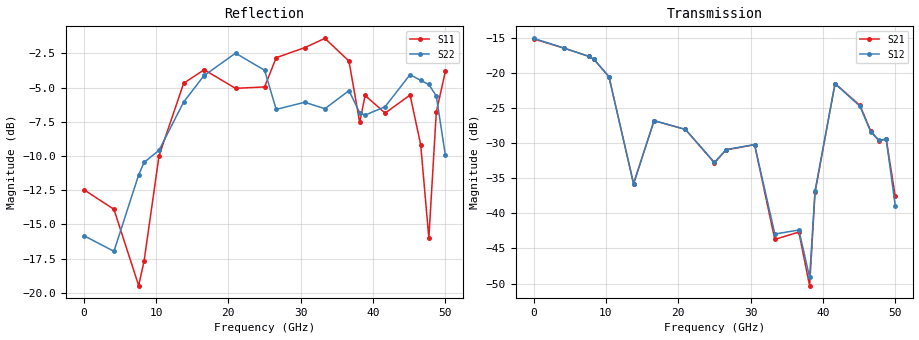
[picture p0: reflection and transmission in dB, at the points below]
!Keysight Technologies,N5245B,MY58422270,A.16.20.02
!Date: Thursday, March 05, 2026 01:11:40
!Correction: S11(C  2-Port  )
!S21(C  2-Port  )
!S12(C  2-Port  )
!S22(C  2-Port  )
!S2P File: Measurements: S11, S21, S12, S22:
# Hz S  dB  R 50
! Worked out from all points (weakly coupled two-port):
!   3201 points, 10 MHz to 50 GHz, reference 50 ohm
!   highest |S21| = -15.19 dB at 10 MHz (marker M1); lowest = -50.3 dB at 38.16 GHz (marker M2)
!   lowest |S11| = -19.5 dB at 7.602 GHz (marker M3), VSWR 1.24, Z = 40.5 - j1.37 ohm
!   |S11| at or under -10 dB: start of sweep to 10.41 GHz; 46.72 GHz to 48.26 GHz (1.535 GHz wide, 3.23 % of centre)
!   |S22| runs from -20.2 to -2.5 dB; largest |S21 - S12| = 0.0035
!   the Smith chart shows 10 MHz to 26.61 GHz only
!   S11 on the Smith chart (normalised r, x): 10 MHz: 1.62, -0.03; 10.41 GHz: 0.54, +0.15; 13.82 GHz: 1.13, +1.52; 16.63 GHz: 1.33, -1.96; 20.99 GHz: 0.33, -0.39; 26.61 GHz: 0.18, +0.30
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1e7  -12.46 -2.3  -15.19 3.4  -15.11 4.4  -15.82 42.8
4.181041e9  -13.90 -131.6  -16.49 -171.4  -16.49 -171.4  -16.97 -110.2
7.602231e9  -19.48 -171.0  -17.66 41.2  -17.65 41.2  -11.38 -159.2
8.352081e9  -17.66 -163.0  -18.11 7.7  -18.09 7.7  -10.47 -176.7
1.041417e10  -9.99 156.0  -20.57 -83.6  -20.55 -83.8  -9.59 116.7
1.381974e10  -4.69 49.7  -35.76 -173.8  -35.83 -174.9  -6.06 -53.8
1.663168e10  -3.71 -40.4  -26.89 160.1  -26.90 160.1  -4.13 -143.3
1.667854e10  -3.71 -41.8  -26.82 158.3  -26.82 158.4  -4.12 -144.3
2.099018e10  -5.06 -133.6  -28.07 24.3  -28.06 24.2  -2.49 139.8
2.5005e10  -4.96 174.6  -32.82 -66.7  -32.76 -66.4  -3.74 70.6
2.661405e10  -2.82 145.6  -30.97 -100.3  -30.93 -100.5  -6.60 39.2
3.055077e10  -2.09 80.1  -30.24 125.4  -30.22 125.9  -6.08 -51.1
3.334708e10  -1.41 35.7  -43.71 -3.5  -42.94 -0.2  -6.55 -132.9
3.667454e10  -3.07 -30.8  -42.66 101.4  -42.37 102.5  -5.23 159.0
3.815862e10  -7.55 -22.7  -50.29 70.4  -49.12 75.7  -6.84 134.0
3.890847e10  -5.58 -29.7  -37.02 101.2  -36.84 100.7  -7.02 137.0
4.167354e10  -6.87 -55.2  -21.53 -57.3  -21.55 -57.3  -6.40 110.3
4.512598e10  -5.55 -101.9  -24.65 85.5  -24.77 85.7  -4.06 74.0
4.659443e10  -9.19 -153.2  -28.26 32.5  -28.37 30.8  -4.48 53.8
4.771921e10  -16.00 69.6  -29.66 -15.1  -29.58 -16.2  -4.78 41.6
4.875025e10  -6.80 -26.5  -29.44 -89.4  -29.46 -88.7  -5.62 20.7
5e10  -3.83 -72.5  -37.59 -117.5  -38.90 -129.3  -9.94 9.3
